One B-rep face of a CAD part: STEP entity #74406.
In plain terms, the planar face has unit normal (0, 0, 1).
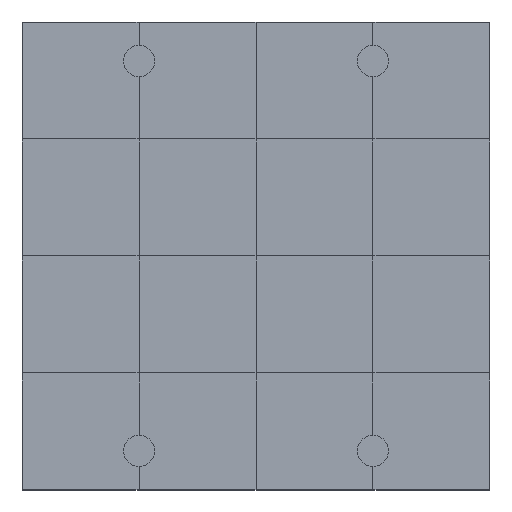
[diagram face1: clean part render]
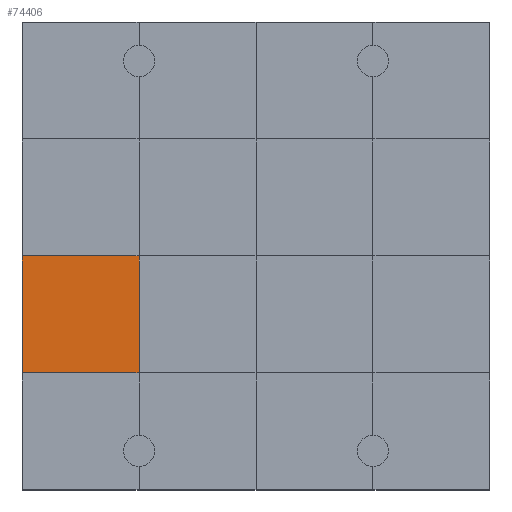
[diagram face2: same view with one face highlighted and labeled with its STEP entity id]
Its self-contained STEP definition (entity closure, numbers rounded to 3 decimals):
#73956 = VERTEX_POINT('',#73957);
#73957 = CARTESIAN_POINT('',(0.,3.,1.2));
#73971 = PLANE('',#73972);
#73972 = AXIS2_PLACEMENT_3D('',#73973,#73974,#73975);
#73973 = CARTESIAN_POINT('',(0.,3.,0.));
#73974 = DIRECTION('',(1.,0.,-0.));
#73975 = DIRECTION('',(0.,0.,1.));
#73997 = PLANE('',#73998);
#73998 = AXIS2_PLACEMENT_3D('',#73999,#74000,#74001);
#73999 = CARTESIAN_POINT('',(0.,0.,1.2));
#74000 = DIRECTION('',(0.,0.,1.));
#74001 = DIRECTION('',(1.,0.,-0.));
#74148 = VERTEX_POINT('',#74149);
#74149 = CARTESIAN_POINT('',(3.,3.,1.2));
#74170 = EDGE_CURVE('',#73956,#74148,#74171,.T.);
#74171 = SURFACE_CURVE('',#74172,(#74176,#74183),.PCURVE_S1.);
#74172 = LINE('',#74173,#74174);
#74173 = CARTESIAN_POINT('',(0.,3.,1.2));
#74174 = VECTOR('',#74175,1.);
#74175 = DIRECTION('',(1.,0.,-0.));
#74176 = PCURVE('',#73997,#74177);
#74177 = DEFINITIONAL_REPRESENTATION('',(#74178),#74182);
#74178 = LINE('',#74179,#74180);
#74179 = CARTESIAN_POINT('',(0.,3.));
#74180 = VECTOR('',#74181,1.);
#74181 = DIRECTION('',(1.,0.));
#74182 = ( GEOMETRIC_REPRESENTATION_CONTEXT(2) 
PARAMETRIC_REPRESENTATION_CONTEXT() REPRESENTATION_CONTEXT('2D SPACE',''
  ) );
#74183 = PCURVE('',#74184,#74189);
#74184 = PLANE('',#74185);
#74185 = AXIS2_PLACEMENT_3D('',#74186,#74187,#74188);
#74186 = CARTESIAN_POINT('',(0.,3.,1.2));
#74187 = DIRECTION('',(0.,0.,1.));
#74188 = DIRECTION('',(1.,0.,-0.));
#74189 = DEFINITIONAL_REPRESENTATION('',(#74190),#74194);
#74190 = LINE('',#74191,#74192);
#74191 = CARTESIAN_POINT('',(0.,0.));
#74192 = VECTOR('',#74193,1.);
#74193 = DIRECTION('',(1.,0.));
#74194 = ( GEOMETRIC_REPRESENTATION_CONTEXT(2) 
PARAMETRIC_REPRESENTATION_CONTEXT() REPRESENTATION_CONTEXT('2D SPACE',''
  ) );
#74229 = VERTEX_POINT('',#74230);
#74230 = CARTESIAN_POINT('',(0.,6.,1.2));
#74256 = EDGE_CURVE('',#73956,#74229,#74257,.T.);
#74257 = SURFACE_CURVE('',#74258,(#74262,#74269),.PCURVE_S1.);
#74258 = LINE('',#74259,#74260);
#74259 = CARTESIAN_POINT('',(0.,3.,1.2));
#74260 = VECTOR('',#74261,1.);
#74261 = DIRECTION('',(-0.,1.,0.));
#74262 = PCURVE('',#73971,#74263);
#74263 = DEFINITIONAL_REPRESENTATION('',(#74264),#74268);
#74264 = LINE('',#74265,#74266);
#74265 = CARTESIAN_POINT('',(1.2,0.));
#74266 = VECTOR('',#74267,1.);
#74267 = DIRECTION('',(0.,-1.));
#74268 = ( GEOMETRIC_REPRESENTATION_CONTEXT(2) 
PARAMETRIC_REPRESENTATION_CONTEXT() REPRESENTATION_CONTEXT('2D SPACE',''
  ) );
#74269 = PCURVE('',#74184,#74270);
#74270 = DEFINITIONAL_REPRESENTATION('',(#74271),#74275);
#74271 = LINE('',#74272,#74273);
#74272 = CARTESIAN_POINT('',(0.,0.));
#74273 = VECTOR('',#74274,1.);
#74274 = DIRECTION('',(0.,1.));
#74275 = ( GEOMETRIC_REPRESENTATION_CONTEXT(2) 
PARAMETRIC_REPRESENTATION_CONTEXT() REPRESENTATION_CONTEXT('2D SPACE',''
  ) );
#74406 = ADVANCED_FACE('',(#74407),#74184,.T.);
#74407 = FACE_BOUND('',#74408,.T.);
#74408 = EDGE_LOOP('',(#74409,#74410,#74411,#74439));
#74409 = ORIENTED_EDGE('',*,*,#74256,.F.);
#74410 = ORIENTED_EDGE('',*,*,#74170,.T.);
#74411 = ORIENTED_EDGE('',*,*,#74412,.T.);
#74412 = EDGE_CURVE('',#74148,#74413,#74415,.T.);
#74413 = VERTEX_POINT('',#74414);
#74414 = CARTESIAN_POINT('',(3.,6.,1.2));
#74415 = SURFACE_CURVE('',#74416,(#74420,#74427),.PCURVE_S1.);
#74416 = LINE('',#74417,#74418);
#74417 = CARTESIAN_POINT('',(3.,3.,1.2));
#74418 = VECTOR('',#74419,1.);
#74419 = DIRECTION('',(-0.,1.,0.));
#74420 = PCURVE('',#74184,#74421);
#74421 = DEFINITIONAL_REPRESENTATION('',(#74422),#74426);
#74422 = LINE('',#74423,#74424);
#74423 = CARTESIAN_POINT('',(3.,0.));
#74424 = VECTOR('',#74425,1.);
#74425 = DIRECTION('',(0.,1.));
#74426 = ( GEOMETRIC_REPRESENTATION_CONTEXT(2) 
PARAMETRIC_REPRESENTATION_CONTEXT() REPRESENTATION_CONTEXT('2D SPACE',''
  ) );
#74427 = PCURVE('',#74428,#74433);
#74428 = PLANE('',#74429);
#74429 = AXIS2_PLACEMENT_3D('',#74430,#74431,#74432);
#74430 = CARTESIAN_POINT('',(3.,3.,1.2));
#74431 = DIRECTION('',(0.,0.,1.));
#74432 = DIRECTION('',(1.,0.,-0.));
#74433 = DEFINITIONAL_REPRESENTATION('',(#74434),#74438);
#74434 = LINE('',#74435,#74436);
#74435 = CARTESIAN_POINT('',(0.,0.));
#74436 = VECTOR('',#74437,1.);
#74437 = DIRECTION('',(0.,1.));
#74438 = ( GEOMETRIC_REPRESENTATION_CONTEXT(2) 
PARAMETRIC_REPRESENTATION_CONTEXT() REPRESENTATION_CONTEXT('2D SPACE',''
  ) );
#74439 = ORIENTED_EDGE('',*,*,#74440,.F.);
#74440 = EDGE_CURVE('',#74229,#74413,#74441,.T.);
#74441 = SURFACE_CURVE('',#74442,(#74446,#74453),.PCURVE_S1.);
#74442 = LINE('',#74443,#74444);
#74443 = CARTESIAN_POINT('',(0.,6.,1.2));
#74444 = VECTOR('',#74445,1.);
#74445 = DIRECTION('',(1.,0.,-0.));
#74446 = PCURVE('',#74184,#74447);
#74447 = DEFINITIONAL_REPRESENTATION('',(#74448),#74452);
#74448 = LINE('',#74449,#74450);
#74449 = CARTESIAN_POINT('',(0.,3.));
#74450 = VECTOR('',#74451,1.);
#74451 = DIRECTION('',(1.,0.));
#74452 = ( GEOMETRIC_REPRESENTATION_CONTEXT(2) 
PARAMETRIC_REPRESENTATION_CONTEXT() REPRESENTATION_CONTEXT('2D SPACE',''
  ) );
#74453 = PCURVE('',#74454,#74459);
#74454 = PLANE('',#74455);
#74455 = AXIS2_PLACEMENT_3D('',#74456,#74457,#74458);
#74456 = CARTESIAN_POINT('',(0.,6.,1.2));
#74457 = DIRECTION('',(0.,0.,1.));
#74458 = DIRECTION('',(1.,0.,-0.));
#74459 = DEFINITIONAL_REPRESENTATION('',(#74460),#74464);
#74460 = LINE('',#74461,#74462);
#74461 = CARTESIAN_POINT('',(0.,0.));
#74462 = VECTOR('',#74463,1.);
#74463 = DIRECTION('',(1.,0.));
#74464 = ( GEOMETRIC_REPRESENTATION_CONTEXT(2) 
PARAMETRIC_REPRESENTATION_CONTEXT() REPRESENTATION_CONTEXT('2D SPACE',''
  ) );
